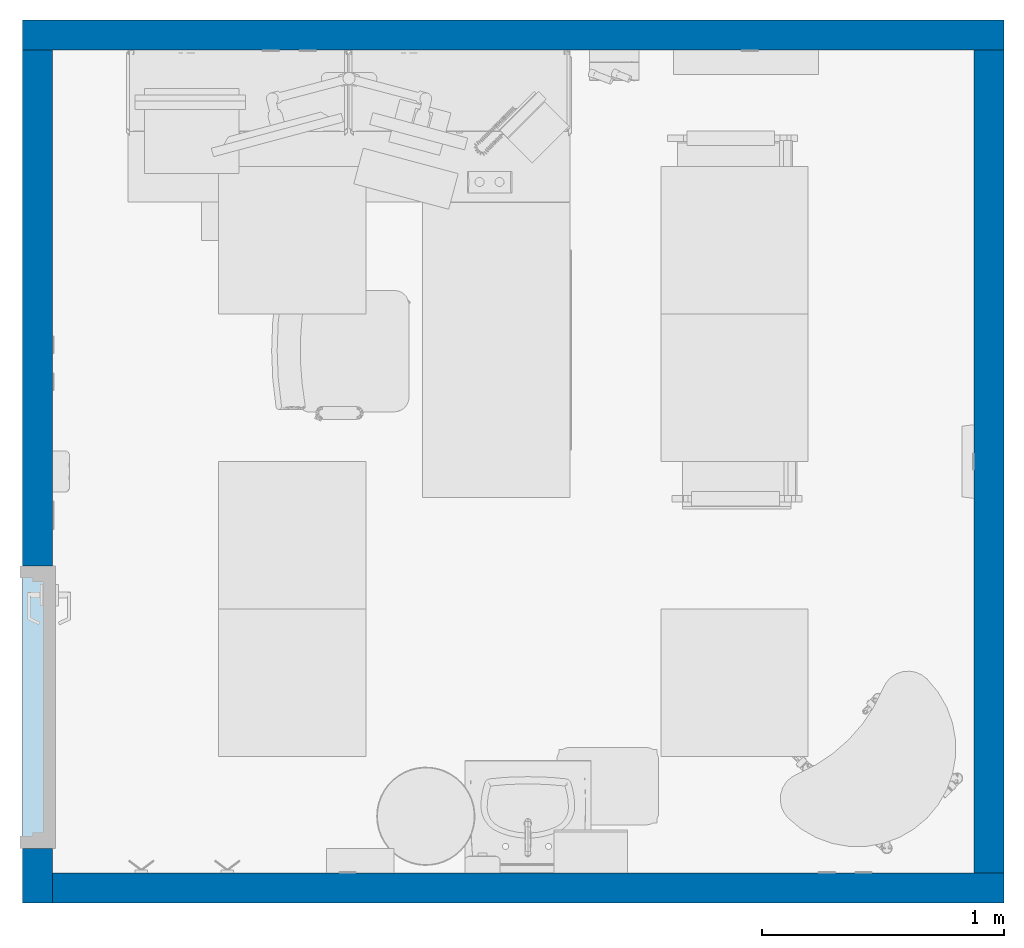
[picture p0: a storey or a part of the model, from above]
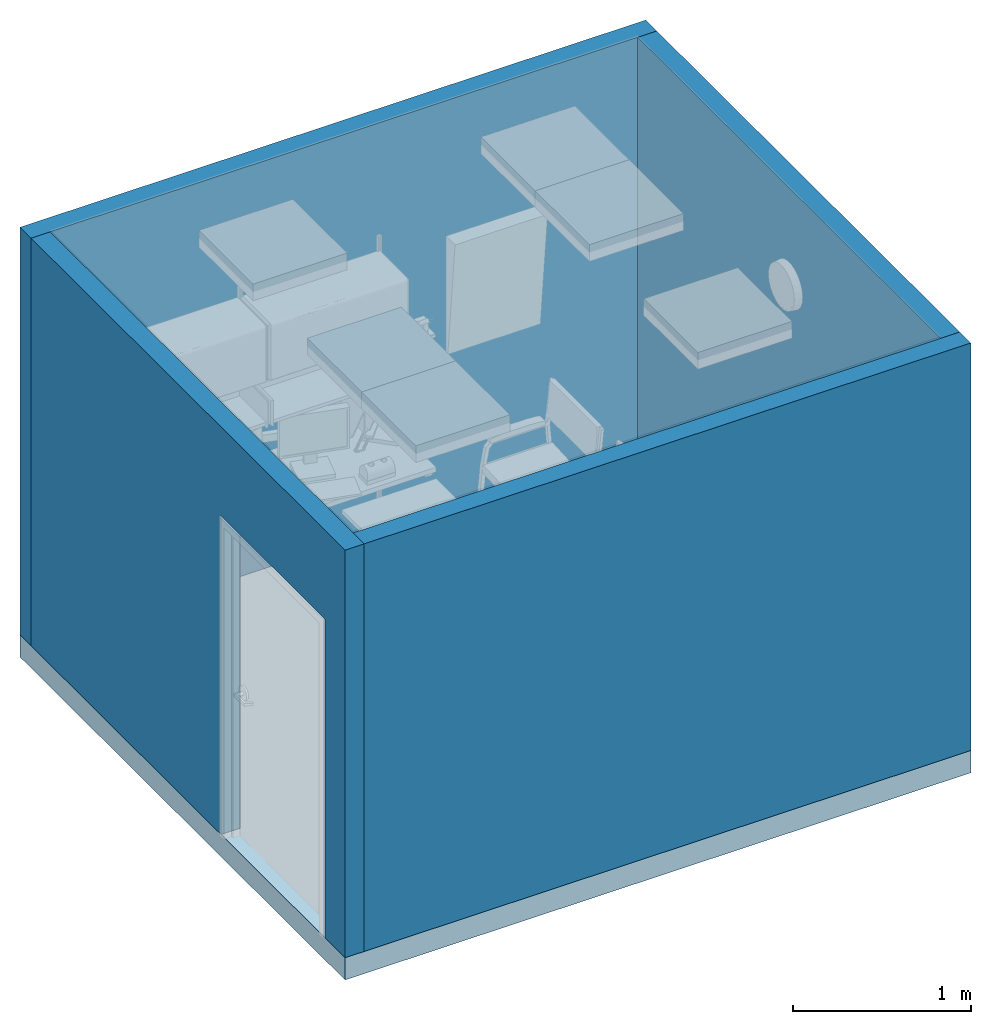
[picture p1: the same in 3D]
Properties of the parts of a building model (IFC2X3)

# File
Description: ViewDefinition [CoordinationView_V2.0]
File name: (ROOM CODE)
Time: 2018-06-28T09:21:54
Written by: The EXPRESS Data Manager Version 5.02.0100.07 : 28 Aug 2013
Made in: 20170223_1515(x64) - Exporter 18.0.0.420 - Alternate UI 18.0.0.420
Comment: STEP Physical File produced by: The EXPRESS Data Manager Version 5.02.0100.07 : 28 Aug 2013 * Module: EDMstepFileFactory/EDMstandAlone * Creation date: Thu Jun 28 09:21:54 2018 * Host: L105-OKC * Database: C:\Users\jet\AppData\Local\Temp\{2E553895-5F6D-4461-8BD8-E5F2F549CAB2}\ifc * Database version: 5507 * Database creation date: Thu Jun 28 09:21:50 2018 * Schema: IFC2X3 * Model: DataRepository.ifc * Model creation date: Thu Jun 28 09:21:51 2018 * Header model: DataRepository.ifc_HeaderModel * Header model creation date: Thu Jun 28 09:21:51 2018 * EDMuser: sdai-user * EDMgroup: sdai-group * License ID and type: 5605 : Permanent license. Expiry date: * EDMstepFileFactory options: 020000

# IfcProject, (ROOM CODE)
LongName: ROOM NAME (ROOM CODE); Phase: DRAFT

# IfcSite, Default
RefLatitude: 42, 21, 31, 181945; RefLongitude: -71, -3, -24, -263305; RefElevation: 0 ft

# IfcBuilding, AUDIOLOGY AND SPEECH PATHOLOGY (Ch. 204)
LongName: AUDIOLOGY AND SPEECH PATHOLOGY (Ch. 204)
Pset_BuildingCommon - NumberOfStoreys: 1

# IfcBuildingStorey, AUD01 - Audiology Rehabilitation/Counseling
In: AUDIOLOGY AND SPEECH PATHOLOGY (Ch. 204)
LongName: AUD01 - Audiology Rehabilitation/Counseling; Elevation: 42 ft

# IfcSpace, (AUD01)
In: AUD01 - Audiology Rehabilitation/Counseling
LongName: AUDIOLOGY REHABILITATION / COUNSELING; InteriorOrExteriorSpace: INTERNAL
Pset_SpaceCommon - Reference: AUDIOLOGY REHABILITATION / COUNSELING (AUD01); Category: Rooms

# IfcBuildingElementProxy: 24" x 24", Supply Diffuser:24" x 24":5452682
In: (AUD01)
Type - Classification: D3040100 Air Distribution Systems (Uniformat)
Pset_BuildingElementProxyCommon - Reference: 24" x 24"

# IfcBuildingElementProxy: 24" x 24", Return Register:24" x 24":5452875
In: (AUD01)
Type - Classification: D3040200 Exhaust Ventilation Systems (Uniformat)
Pset_BuildingElementProxyCommon - Reference: 24" x 24"

# IfcBuildingElementProxy: A1016 - Telephone, Desk, With Speaker 12 x 12, A1016 - Telephone, Desk, With Speaker:A1016 - Telephone, Desk, With Speaker 12 x 12:5441735
In: (AUD01)
Type - Classification: VV (Uniformat)
Pset_BuildingElementProxyCommon - Reference: A1016 - Telephone, Desk, With Speaker 12 x 12

# IfcBuildingElementProxy: A1067 - Mirror, Float Glass, ADA Accessible, A1067 - Mirror, Float Glass, ADA Accessible:A1067 - Mirror, Float Glass, ADA Accessible:5453417
In: (AUD01)
Type - Classification: CC (Uniformat)
Pset_BuildingElementProxyCommon - Reference: A1067 - Mirror, Float Glass, ADA Accessible

# IfcBuildingElementProxy: A5075 - Dispenser, Soap, Disposable, A5075 - Dispenser, Soap, Disposable:A5075 - Dispenser, Soap, Disposable:4419849
In: (AUD01)
Type - Classification: VV (Uniformat)
Pset_BuildingElementProxyCommon - Reference: A5075 - Dispenser, Soap, Disposable

# IfcBuildingElementProxy: A5077 - Dispenser, Hand Sanitizer, Hands free, A5077 - Dispenser, Hand Sanitizer, Hands free:A5077 - Dispenser, Hand Sanitizer, Hands free:2899999
In: (AUD01)
Type - Classification: VV (Uniformat)
Pset_BuildingElementProxyCommon - Reference: A5077 - Dispenser, Hand Sanitizer, Hands free

# IfcBuildingElementProxy: A5082 - Dispenser, Paper Towel, Sensor, Hands Free, A5082 - Dispenser, Paper Towel, Sensor, Hands Free:A5082 - Dispenser, Paper Towel, Sensor, Hands Free:3483639
In: (AUD01)
Type - Classification: CC (Uniformat)
Pset_BuildingElementProxyCommon - Reference: A5082 - Dispenser, Paper Towel, Sensor, Hands Free

# IfcBuildingElementProxy: A5107 - Dispenser, Glove, Surgical-Examination, Wall Mntd, A5107 - Dispenser, Glove, Surgical-Examination, Wall Mntd:A5107 - Dispenser, Glove, Surgical-Examination, Wall Mntd:5559900
In: (AUD01)
Type - Classification: VV (Uniformat)
Pset_BuildingElementProxyCommon - Reference: A5107 - Dispenser, Glove, Surgical-Examination, Wall Mntd

# IfcBuildingElementProxy: A5108 - Waste Disposal Unit, Sharps, A5108 - Waste Disposal Unit, Sharps:A5108 - Waste Disposal Unit, Sharps:4419850
In: (AUD01)
Type - Classification: VV (Uniformat)
Pset_BuildingElementProxyCommon - Reference: A5108 - Waste Disposal Unit, Sharps

# IfcBuildingElementProxy: A5145 - Hook, Garment, Double 4" x 2" Typical Height (5'-6") (2)
In: (AUD01)
Type - Classification: CC (Uniformat)
Pset_BuildingElementProxyCommon - Reference: A5145 - Hook, Garment, Double 4" x 2" Typical Height (5'-6")
Name (A5145 - Hook, Garment, Double, SS, Surface Mounted:A5145 - Hook, Garment, Double 4" x 2" Typical Height (5'-6"):...)
4969716
5169236

# IfcBuildingElementProxy: A5225 - Dual Flat Panel Monitor ARMS, A5225 - Bracket, Dual Computer Monitor, Desk-Mounted:A5225 - Dual Flat Panel Monitor ARMS:4972586
In: (AUD01)
Type - Classification: VV (Uniformat)
Pset_BuildingElementProxyCommon - Reference: A5225 - Dual Flat Panel Monitor ARMS

# IfcBuildingElementProxy: Double, Switch, Multiple:Double:5466406
In: (AUD01)
Pset_BuildingElementProxyCommon - Reference: Double

# IfcBuildingElementProxy: Duplex (6)
In: (AUD01)
Pset_BuildingElementProxyCommon - Reference: Duplex
Name (Outlet, Duplex, Wall:Duplex:...)
5620137
5563877
5560207
5563476
5563802
5563679

# IfcBuildingElementProxy: F0205 - Chair, Side With Arms, F0205 - Chair, Side With Arms:F0205 - Chair, Side With Arms:3809383
In: (AUD01)
Type - Classification: VV (Uniformat)
Pset_BuildingElementProxyCommon - Reference: F0205 - Chair, Side With Arms

# IfcBuildingElementProxy: F0206 - Chair, Side, Bariatric, With Arms, F0206 - Chair, Side, Bariatric, With Arms:F0206 - Chair, Side, Bariatric, With Arms:2876612
In: (AUD01)
Type - Classification: VV (Uniformat)
Pset_BuildingElementProxyCommon - Reference: F0206 - Chair, Side, Bariatric, With Arms

# IfcBuildingElementProxy: F0280 - Chair, Swivel, Low Back, F0280 - Chair, Swivel, Low Back:F0280 - Chair, Swivel, Low Back:3468958
In: (AUD01)
Type - Classification: VV (Uniformat)
Pset_BuildingElementProxyCommon - Reference: F0280 - Chair, Swivel, Low Back

# IfcBuildingElementProxy: F0865 - Table, Adjustable Height, 48x24, F0865 - Table, Adjustable Height, 48x24:F0865 - Table, Adjustable Height, 48x24:5117606
In: (AUD01)
Type - Classification: VV (Uniformat)
Pset_BuildingElementProxyCommon - Reference: F0865 - Table, Adjustable Height, 48x24

# IfcBuildingElementProxy: F2247 - Magnifier, Video, Desktop, F2247 - Magnifier, Video, Desktop:F2247 - Magnifier, Video, Desktop:5447555
In: (AUD01)
Type - Classification: VV (Uniformat)
Pset_BuildingElementProxyCommon - Reference: F2247 - Magnifier, Video, Desktop
Pset_ManufacturerTypeInformation - Manufacturer: INFORMATION SYSTEMS TO SPECIFY

# IfcBuildingElementProxy: F3200 - Clock, Battery, 12in Dia, F3200 - Clock, Battery, 12in Diameter:F3200 - Clock, Battery, 12in Dia:5454106
In: (AUD01)
Type - Classification: VV (Uniformat)
Pset_BuildingElementProxyCommon - Reference: F3200 - Clock, Battery, 12in Dia

# IfcBuildingElementProxy: M0525 - TABLE, M0525 - Table, Mobile, Adjustable Height:M0525 - TABLE:5161238
In: (AUD01)
Type - Classification: VV (Uniformat)
Pset_BuildingElementProxyCommon - Reference: M0525 - TABLE
Pset_ManufacturerTypeInformation - Manufacturer: Midmark

# IfcBuildingElementProxy: M1800 - Monitor, Computer, M1800 - Monitor, Computer:M1800 - Monitor, Computer:4976539
In: (AUD01)
Type - Classification: VV (Uniformat)
Pset_BuildingElementProxyCommon - Reference: M1800 - Monitor, Computer

# IfcBuildingElementProxy: M1801 - Computer, Microprocessing, With Flat Panel Monitor, M1801 - Computer, Microprocessing, With Flat Panel Monitor:M1801 - Computer, Microprocessing, With Flat Panel Monitor:4978491
In: (AUD01)
Type - Classification: VV (Uniformat)
Pset_BuildingElementProxyCommon - Reference: M1801 - Computer, Microprocessing, With Flat Panel Monitor

# IfcBuildingElementProxy: M4200 - Otoscope / Ophthalmoscope, Wall Mounted, M4200 - Otoscope-Ophthalmoscope, Wall Mounted:M4200 - Otoscope / Ophthalmoscope, Wall Mounted:5343879
In: (AUD01)
Type - Classification: VV (Uniformat)
Pset_BuildingElementProxyCommon - Reference: M4200 - Otoscope / Ophthalmoscope, Wall Mounted

# IfcBuildingElementProxy: M4200 - Otoscope, Diagnostic, Desk-mounted, M4200 - Otoscope, Diagnostic, Desk-mounted:M4200 - Otoscope, Diagnostic, Desk-mounted:5149302
In: (AUD01)
Type - Classification: VV (Uniformat)
Pset_BuildingElementProxyCommon - Reference: M4200 - Otoscope, Diagnostic, Desk-mounted

# IfcBuildingElementProxy: P3200 - Lavatory, Viteous China, Slab Type WSens Op Fauc 20"x 18", P3200 - Lavatory, Vitreous China, Slab Type w Sens Op Fauc:P3200 - Lavatory, Viteous China, Slab Type WSens Op Fauc 20"x 18":4965235
In: (AUD01)
Type - Classification: CC (Uniformat)
Pset_BuildingElementProxyCommon - Reference: P3200 - Lavatory, Viteous China, Slab Type WSens Op Fauc 20"x 18"

# IfcBuildingElementProxy: Round, Metal, F2000 - Basket, Wastepaper:Round, Metal:4974853
In: (AUD01)
Type - Classification: VV (Uniformat)
Pset_BuildingElementProxyCommon - Reference: Round, Metal

# IfcBuildingElementProxy: Telephone/Data (3)
In: (AUD01)
Pset_BuildingElementProxyCommon - Reference: Telephone/Data
Name (Outlet, Communications:Telephone/Data:...)
5560259
5563516
5563617

# IfcBuildingElementProxy: w/Overhead Cab, Wall Mtd, 72" W, E0226 - Worksurface, Computer, O-H Cab, Wall Mtd, 72in - 2:w/Overhead Cab, Wall Mtd, 72" W:5447246
In: (AUD01)
Type - Classification: VV (Uniformat)
Pset_BuildingElementProxyCommon - Reference: w/Overhead Cab, Wall Mtd, 72" W

# IfcCovering: Compound Ceiling:2' x 2' ACT System, Compound Ceiling:2' x 2' ACT System:3443880
In: (AUD01)
PredefinedType: CEILING; Classification: C3030210 Suspended Ceilings - Acoustical (Uniformat); Material: <Unnamed> 0.166667 ft, act 0.0416667 ft
Pset_CoveringCommon - Reference: 2' x 2' ACT System; Finish: act;; TotalThickness: 0.208333 ft

# IfcDoor: 42" x 84", Single - Flush:42" x 84":2540561
In: AUD01 - Audiology Rehabilitation/Counseling
Type - ParameterTakesPrecedence: no; Sizeable: no; Classification: C1020 Interior Doors (Uniformat)
OverallHeight: 7.16667 ft; OverallWidth: 3.83333 ft
Pset_DoorCommon - Reference: 42" x 84"; IsExternal: no

# IfcFlowTerminal: 2'x2' (4)
In: (AUD01)
Type - Classification: D5020210 Lighting - Fluorescent (Uniformat)
Pset_DistributionFlowElementCommon - Reference: 2'x2'
Name (Troffer Light:2'x2':...)
5452356
5452629
5452677
5452678

# IfcSlab: Floor:Generic - 6", Floor:Generic - 6":2793947
In: AUD01 - Audiology Rehabilitation/Counseling
PredefinedType: FLOOR; Classification: B1010 Floor Construction (Uniformat); Material: <Unnamed> 0.5 ft
Pset_SlabCommon - IsExternal: no; Reference: Generic - 6"; LoadBearing: no; PitchAngle: 0 deg

# IfcWallStandardCase: Basic Wall:Interior - 4 7/8" (4)
In: AUD01 - Audiology Rehabilitation/Counseling
Type - PredefinedType: STANDARD; Material: <Unnamed> 0.40625 ft
Classification: B2010 Exterior Walls (Uniformat)
Pset_WallCommon - LoadBearing: no; Reference: Interior - 4 7/8"; ExtendToStructure: no; IsExternal: yes
Name (Basic Wall:Interior - 4 7/8":...)
5400213
5400315
5400585
5400645
